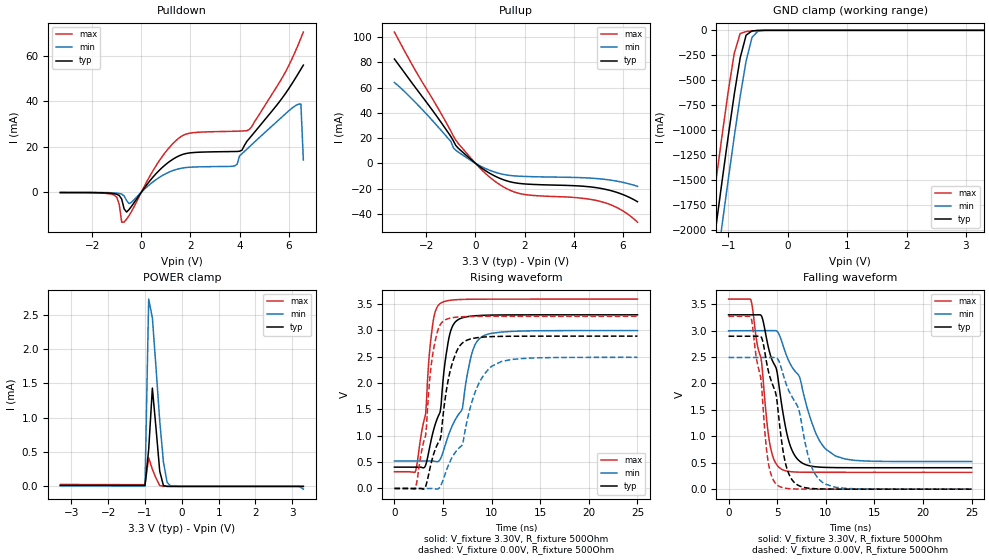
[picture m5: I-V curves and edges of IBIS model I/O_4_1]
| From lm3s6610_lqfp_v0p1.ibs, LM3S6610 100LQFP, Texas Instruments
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[Model]   I/O_4_1
Model_type   I/O
Vinl = 1.26
Vinh = 2.04
Vmeas = 1.65
| variable   typ   min   max
C_comp   9.739pF   9.739pF   9.739pF
[Model Spec]
Vinh+   1.91   1.78   2.04
Vinh-   1.90   1.76   2.03
Vinl+   1.40   1.27   1.54
Vinl-   1.39   1.26   1.53
| variable   typ   min   max
[Temperature Range]  25   85   -40
[Voltage Range]   3.3V   3.0V   3.6V
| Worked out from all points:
|   slope of the pulldown table from 0 to 0.495 V, typ, clamps not added: 71.5 ohm
|   slope of the pullup table from 0 to 0.495 V, typ, clamps not added: 71.6 ohm
|   GND clamp passes 1 mA (typ) near -0.48 V on its own axis
|   POWER clamp passes 1 mA (typ) near -0.73 V on its own axis
|   falling waveform, V_fixture 3.30V, R_fixture 500Ohm: 20-80 % time 2.03ns typ, 3.06ns min, 1.36ns max; typ from 3.3 V to 0.405 V
|   rising waveform, V_fixture 3.30V, R_fixture 500Ohm: 20-80 % time 1.61ns typ, 2.31ns min, 1.11ns max; typ from 0.405 V to 3.3 V
|   falling waveform, V_fixture 0.00V, R_fixture 500Ohm: 20-80 % time 1.75ns typ, 2.48ns min, 1.21ns max; typ from 2.89 V to 0 V
|   rising waveform, V_fixture 0.00V, R_fixture 500Ohm: 20-80 % time 1.94ns typ, 2.99ns min, 1.26ns max; typ from 0 V to 2.89 V
[Pulldown]
|  Voltage   I(typ)   I(min)   I(max)
-3.3V     -128.3uA   -72.81uA   -182.3uA
-1.1V     -636.5uA   -293.8uA   -1.284mA
-800mV    -2.996mA   -835.1uA   -13.2mA
-700mV    -7.355mA   -1.607mA   -13.16mA
-500mV    -7.628mA   -5mA       -10.33mA
700mV     9.309mA    6.304mA    13.37mA
1.6V      16.33mA    10.51mA    24.41mA
3.8V      17.94mA    11.61mA    26.87mA
4.4V      23.7mA     20mA       27.72mA
6.4V      52.42mA    38.8mA     65.24mA
6.5V      54.21mA    38.87mA    67.86mA
6.6V      56.01mA    14.21mA    70.56mA
[Pullup]
|  Voltage   I(typ)   I(min)   I(max)
-3.3V     82.57mA    63.94mA    103.9mA
-1.8V     43.25mA    34.86mA    52.68mA
-1V       21.14mA    17.2mA     25.44mA
-900mV    17.77mA    12.26mA    21.52mA
-800mV    14.06mA    10.32mA    18.34mA
100mV     -1.553mA   -1.117mA   -2.117mA
700mV     -9.22mA    -6.424mA   -12.9mA
1.3V      -14.07mA   -9.367mA   -20.37mA
1.9V      -16.2mA    -10.35mA   -24.39mA
5.2V      -20.26mA   -12.6mA    -30.84mA
5.9V      -24.02mA   -14.69mA   -36.54mA
6.6V      -30.45mA   -18.28mA   -46.68mA
[GND Clamp]
|  Voltage   I(typ)   I(min)   I(max)
-3.3V     -11.72A    -12.12A    -11.3A
-1.4V     -2.845A    -3.285A    -2.387A
-1.3V     -2.39A     -2.831A    -1.93A
-1.2V     -1.938A    -2.38A     -1.478A
-1.1V     -1.494A    -1.934A    -1.036A
-1V       -1.059A    -1.496A    -610.6mA
-900mV    -645mA     -1.069A    -232.9mA
-800mV    -277.1mA   -664.4mA   -31.59mA
-700mV    -48.56mA   -306.6mA   -12.09mA
-600mV    -5.558mA   -70.2mA    -6.272mA
-500mV    -1.167mA   -7.88mA    -2.167mA
3.3V      2.282nA    3.101uA    451.3pA
[POWER Clamp]
|  Voltage   I(typ)   I(min)   I(max)
-3.3V     15.18uA    8.315uA    27.48uA
-1V       14.14uA    7.74uA     25.63uA
-900mV    536uA      2.726mA    416.7uA
-800mV    1.43mA     2.454mA    247.6uA
-700mV    840.7uA    1.719mA    119.9uA
-600mV    221.2uA    951.5uA    11.58uA
-500mV    12.35uA    355.6uA    955.3nA
-400mV    305.2nA    58.59uA    44.3nA
-300mV    9.515nA    3.101uA    1.472nA
3.1V      1.302nA    -112.7nA   143.5pA
3.2V      1.207nA    -2.287uA   131.7pA
3.3V      -104.8pA   -40.34uA   119.2pA
[Ramp]
| variable   typ   min   max
dV/dt_f   1.73/2.03n   1.48/3.06n   1.97/1.36n
dV/dt_r   1.74/1.94n   1.49/2.99n   1.96/1.26n
R_load = 500Ohm
[Falling Waveform]
V_fixture = 3.30V
V_fixture_min = 3.00V
V_fixture_max = 3.60V
R_fixture = 500Ohm
|   Time   V(typ)   V(min)   V(max)
0s        3.297V     2.995V     3.595V
2.3ns     3.297V     2.998V     3.582V
3.4ns     3.272V     2.998V     2.405V
4.2ns     2.605V     2.998V     904.5mV
5.3ns     1.806V     2.883V     396.4mV
6.1ns     972.7mV    2.465V     338.5mV
6.9ns     612mV      2.217V     324.2mV
9.1ns     420.8mV    1.008V     318.9mV
11ns      407.6mV    627mV      318.6mV
25ns      405.4mV    522.4mV    318.5mV
[Rising Waveform]
V_fixture = 3.30V
V_fixture_min = 3.00V
V_fixture_max = 3.60V
R_fixture = 500Ohm
|   Time   V(typ)   V(min)   V(max)
0s        405.4mV    522.4mV    318.5mV
2.2ns     405.4mV    522.4mV    343mV
3.2ns     435.5mV    522.4mV    1.4V
3.6ns     760.2mV    522.3mV    2.571V
4ns       1.092V     521.2mV    3.195V
4.7ns     1.449V     551.8mV    3.511V
5.2ns     2.388V     807.4mV    3.554V
5.9ns     3.051V     1.172V     3.578V
9ns       3.287V     2.881V     3.595V
25ns      3.298V     2.999V     3.597V
[Falling Waveform]
V_fixture = 0.00V
V_fixture_min = 0.00V
V_fixture_max = 0.00V
R_fixture = 500Ohm
|   Time   V(typ)   V(min)   V(max)
0s        2.893V     2.49V      3.27V
2.3ns     2.893V     2.491V     3.256V
3.3ns     2.891V     2.491V     2.119V
4.1ns     2.228V     2.491V     489.2mV
5.1ns     1.475V     2.451V     66.07mV
5.7ns     623.8mV    2.118V     22.43mV
6.4ns     215mV      1.79V      7.113mV
8.5ns     13.49mV    445.2mV    479.7uV
9.7ns     3.634mV    124.5mV    177.5uV
25ns      17.27uV    28.07uV    10.86uV
[Rising Waveform]
V_fixture = 0.00V
V_fixture_min = 0.00V
V_fixture_max = 0.00V
R_fixture = 500Ohm
|   Time   V(typ)   V(min)   V(max)
0s        192.1uV    3.96mV     11.02uV
2.2ns     30.32uV    819.7uV    27.43mV
3.2ns     33.68mV    421.4uV    997.8mV
4ns       634.4mV    -846uV     2.619V
4.7ns     927.2mV    32.83mV    3.106V
5.1ns     1.54V      213mV      3.188V
6.7ns     2.703V     778mV      3.258V
8.4ns     2.86V      1.876V     3.267V
10ns      2.884V     2.319V     3.269V
25ns      2.893V     2.49V      3.269V
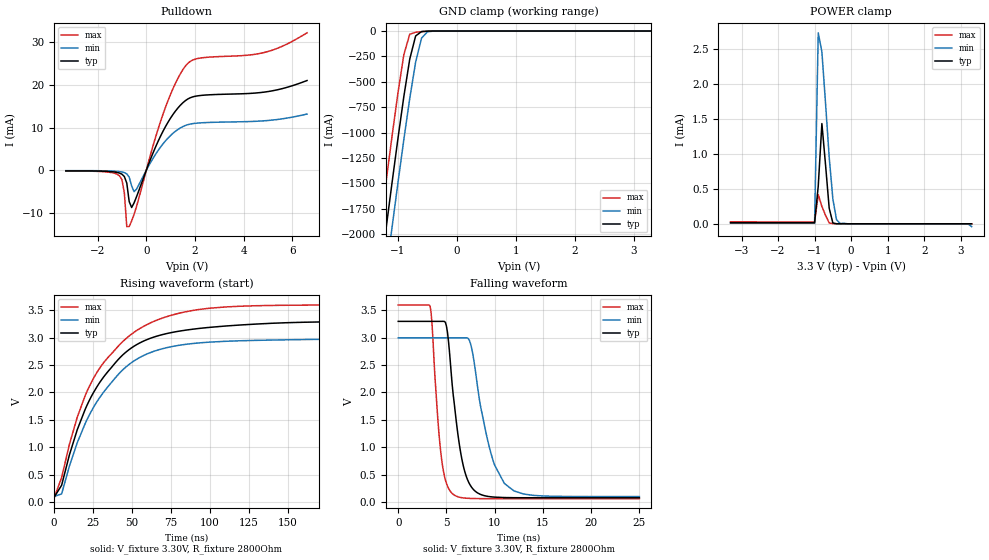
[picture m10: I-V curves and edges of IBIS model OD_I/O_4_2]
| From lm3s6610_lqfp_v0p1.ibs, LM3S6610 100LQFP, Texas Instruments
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[Model]   OD_I/O_4_2
Model_type   I/O_open_drain
Polarity   Inverting
Vinl = 1.26
Vinh = 2.04
Vmeas = 1.65
Rref = 2800
Vref = 3.3
| variable   typ   min   max
C_comp   9.739pF   9.739pF   9.739pF
[Model Spec]
Vinh+   1.91   1.78   2.04
Vinh-   1.90   1.76   2.03
Vinl+   1.40   1.27   1.54
Vinl-   1.39   1.26   1.53
| variable   typ   min   max
[Temperature Range]  25   85   -40
[Voltage Range]   3.3V   3.0V   3.6V
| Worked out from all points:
|   slope of the pulldown table from 0 to 0.495 V, typ, clamps not added: 71.5 ohm
|   GND clamp passes 1 mA (typ) near -0.48 V on its own axis
|   POWER clamp passes 1 mA (typ) near -0.73 V on its own axis
|   falling waveform, V_fixture 3.30V, R_fixture 2800Ohm: 20-80 % time 1.32ns typ, 2ns min, 885ps max; typ from 3.3 V to 0.075 V
|   rising waveform, V_fixture 3.30V, R_fixture 2800Ohm: 20-80 % time 34.3ns typ, 34ns min, 35.2ns max; typ from 0.075 V to 3.3 V
[Pulldown]
|  Voltage   I(typ)   I(min)   I(max)
-3.3V     -128.3uA   -72.81uA   -182.3uA
-1.1V     -636.5uA   -293.8uA   -1.284mA
-900mV    -1.443mA   -530.4uA   -5.27mA
-800mV    -2.996mA   -835.1uA   -13.2mA
-700mV    -7.355mA   -1.607mA   -13.16mA
-600mV    -8.716mA   -3.66mA    -11.87mA
-500mV    -7.628mA   -5mA       -10.33mA
700mV     9.309mA    6.304mA    13.37mA
1.2V      13.92mA    9.18mA     20.46mA
1.7V      16.72mA    10.71mA    25.07mA
4.9V      18.4mA     11.65mA    27.73mA
6.6V      21.07mA    13.21mA    32.27mA
[GND Clamp]
|  Voltage   I(typ)   I(min)   I(max)
-3.3V     -11.72A    -12.12A    -11.3A
-1.4V     -2.845A    -3.285A    -2.387A
-1.3V     -2.39A     -2.831A    -1.93A
-1.2V     -1.938A    -2.38A     -1.478A
-1.1V     -1.494A    -1.934A    -1.036A
-1V       -1.059A    -1.496A    -610.6mA
-900mV    -645mA     -1.069A    -232.9mA
-800mV    -277.1mA   -664.4mA   -31.59mA
-700mV    -48.56mA   -306.6mA   -12.09mA
-600mV    -5.558mA   -70.2mA    -6.272mA
-500mV    -1.167mA   -7.88mA    -2.167mA
3.3V      2.282nA    3.101uA    451.3pA
[POWER Clamp]
|  Voltage   I(typ)   I(min)   I(max)
-3.3V     15.18uA    8.315uA    27.48uA
-1V       14.14uA    7.74uA     25.63uA
-900mV    536uA      2.726mA    416.7uA
-800mV    1.43mA     2.454mA    247.6uA
-700mV    840.7uA    1.719mA    119.9uA
-600mV    221.2uA    951.5uA    11.58uA
-500mV    12.35uA    355.6uA    955.3nA
-400mV    305.2nA    58.59uA    44.3nA
-300mV    9.515nA    3.101uA    1.472nA
3.1V      1.302nA    -112.7nA   143.5pA
3.2V      1.207nA    -2.287uA   131.7pA
3.3V      -104.8pA   -40.34uA   119.2pA
[Ramp]
| variable   typ   min   max
dV/dt_f   1.93/1.32n   1.74/2.00n   2.12/0.89n
dV/dt_r   1.93/34.28n   1.74/34.01n   2.12/35.19n
R_load = 2800Ohm
[Falling Waveform]
V_fixture = 3.30V
V_fixture_min = 3.00V
V_fixture_max = 3.60V
R_fixture = 2800Ohm
|   Time   V(typ)   V(min)   V(max)
0s        3.3V       2.999V     3.6V
3.3ns     3.3V       2.999V     3.58V
4.5ns     3.3V       2.999V     778.2mV
5.1ns     3.106V     2.999V     293mV
5.7ns     1.96V      2.999V     139mV
6.5ns     875.4mV    2.999V     79.96mV
7.3ns     360.9mV    2.976V     64.99mV
9.4ns     98.12mV    1.034V     59.11mV
11ns      79.42mV    338.6mV    58.76mV
25ns      75.03mV    97.58mV    58.6mV
[Rising Waveform]
V_fixture = 3.30V
V_fixture_min = 3.00V
V_fixture_max = 3.60V
R_fixture = 2800Ohm
|   Time   V(typ)   V(min)   V(max)
0s        74.96mV    97.49mV    58.55mV
5ns       304.3mV    145.8mV    444.4mV
10ns      859.9mV    656.9mV    1.053V
15ns      1.317V     1.08V      1.546V
25ns      1.977V     1.706V     2.235V
43ns      2.653V     2.38V      2.896V
60ns      2.969V     2.707V     3.244V
82ns      3.128V     2.869V     3.459V
110ns     3.214V     2.935V     3.562V
250ns     3.298V     2.994V     3.599V
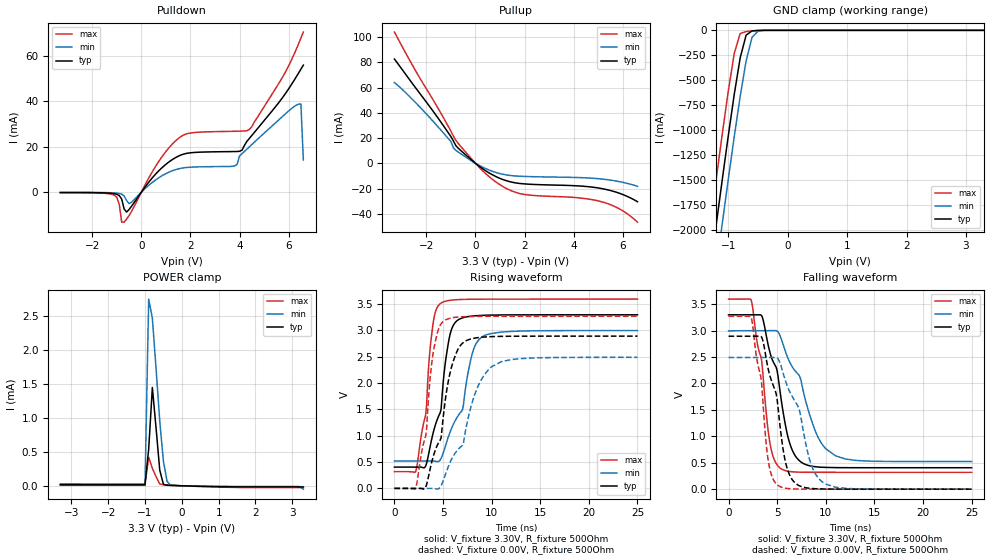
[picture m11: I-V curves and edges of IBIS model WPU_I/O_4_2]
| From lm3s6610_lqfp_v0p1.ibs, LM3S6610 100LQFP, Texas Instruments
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[Model]   WPU_I/O_4_2
Model_type   I/O
Vinl = 1.26
Vinh = 2.04
Vmeas = 1.65
| variable   typ   min   max
C_comp   9.739pF   9.739pF   9.739pF
[Model Spec]
Vinh+   1.91   1.78   2.04
Vinh-   1.90   1.76   2.03
Vinl+   1.40   1.27   1.54
Vinl-   1.39   1.26   1.53
| variable   typ   min   max
[Temperature Range]  25   85   -40
[Voltage Range]   3.3V   3.0V   3.6V
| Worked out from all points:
|   slope of the pulldown table from 0 to 0.495 V, typ, clamps not added: 71.5 ohm
|   slope of the pullup table from 0 to 0.495 V, typ, clamps not added: 71.7 ohm
|   GND clamp passes 1 mA (typ) near -0.48 V on its own axis
|   POWER clamp passes 1 mA (typ) near -0.73 V on its own axis
|   falling waveform, V_fixture 3.30V, R_fixture 500Ohm: 20-80 % time 2.03ns typ, 3.06ns min, 1.36ns max; typ from 3.3 V to 0.405 V
|   rising waveform, V_fixture 3.30V, R_fixture 500Ohm: 20-80 % time 1.62ns typ, 2.31ns min, 1.11ns max; typ from 0.405 V to 3.3 V
|   falling waveform, V_fixture 0.00V, R_fixture 500Ohm: 20-80 % time 1.75ns typ, 2.48ns min, 1.21ns max; typ from 2.89 V to 0 V
|   rising waveform, V_fixture 0.00V, R_fixture 500Ohm: 20-80 % time 1.94ns typ, 2.99ns min, 1.26ns max; typ from 0 V to 2.89 V
[Pulldown]
|  Voltage   I(typ)   I(min)   I(max)
-3.3V     -128.1uA   -72.69uA   -182uA
-1.1V     -635.5uA   -293.2uA   -1.281mA
-800mV    -2.994mA   -834.1uA   -13.19mA
-700mV    -7.352mA   -1.606mA   -13.14mA
-500mV    -7.614mA   -4.997mA   -10.31mA
700mV     9.325mA    6.314mA    13.4mA
1.6V      16.34mA    10.52mA    24.44mA
3.8V      17.93mA    11.6mA     26.87mA
4.4V      23.7mA     20mA       27.71mA
6.4V      52.42mA    38.8mA     65.24mA
6.5V      54.21mA    38.87mA    67.86mA
6.6V      56.01mA    14.21mA    70.56mA
[Pullup]
|  Voltage   I(typ)   I(min)   I(max)
-3.3V     82.57mA    63.94mA    103.9mA
-1.8V     43.25mA    34.86mA    52.68mA
-1V       21.14mA    17.2mA     25.44mA
-900mV    17.77mA    12.24mA    21.52mA
-800mV    14.04mA    10.31mA    18.34mA
100mV     -1.551mA   -1.116mA   -2.115mA
700mV     -9.21mA    -6.417mA   -12.88mA
1.3V      -14.06mA   -9.358mA   -20.34mA
1.9V      -16.18mA   -10.35mA   -24.37mA
5.2V      -20.25mA   -12.6mA    -30.83mA
5.9V      -24.01mA   -14.69mA   -36.53mA
6.6V      -30.45mA   -18.28mA   -46.68mA
[GND Clamp]
|  Voltage   I(typ)   I(min)   I(max)
-3.3V     -11.72A    -12.12A    -11.3A
-1.4V     -2.845A    -3.285A    -2.387A
-1.3V     -2.39A     -2.831A    -1.93A
-1.2V     -1.938A    -2.38A     -1.478A
-1.1V     -1.494A    -1.934A    -1.036A
-1V       -1.059A    -1.496A    -610.6mA
-900mV    -645mA     -1.069A    -232.9mA
-800mV    -277.1mA   -664.4mA   -31.6mA
-700mV    -48.56mA   -306.6mA   -12.11mA
-600mV    -5.565mA   -70.2mA    -6.295mA
-500mV    -1.181mA   -7.883mA   -2.191mA
3.3V      2.282nA    6.919uA    -6.845uA
[POWER Clamp]
|  Voltage   I(typ)   I(min)   I(max)
-3.3V     15.18uA    8.315uA    27.48uA
-1V       14.14uA    7.74uA     25.63uA
-900mV    539.2uA    2.746mA    419.4uA
-800mV    1.446mA    2.463mA    255uA
-700mV    851uA      1.726mA    135.8uA
-600mV    231.3uA    957.3uA    27.23uA
-500mV    21.69uA    361.2uA    14.14uA
-400mV    7.764uA    63.51uA    10.49uA
-300mV    5.5uA      6.919uA    7.727uA
3.1V      -16.64uA   -9.947uA   -27.43uA
3.2V      -16.65uA   -12.11uA   -27.44uA
3.3V      -16.65uA   -49.87uA   -27.45uA
[Ramp]
| variable   typ   min   max
dV/dt_f   1.73/2.03n   1.48/3.06n   1.97/1.36n
dV/dt_r   1.74/1.94n   1.49/2.99n   1.96/1.26n
R_load = 500Ohm
[Falling Waveform]
V_fixture = 3.30V
V_fixture_min = 3.00V
V_fixture_max = 3.60V
R_fixture = 500Ohm
|   Time   V(typ)   V(min)   V(max)
0s        3.297V     2.994V     3.595V
2.3ns     3.297V     2.997V     3.59V
3.4ns     3.283V     2.998V     2.441V
4.3ns     2.559V     2.998V     826.9mV
5.3ns     1.846V     2.901V     400mV
6.1ns     994.8mV    2.482V     339.4mV
6.9ns     620.2mV    2.226V     324.5mV
9.2ns     419.7mV    985.1mV    318.8mV
11ns      407.7mV    630.6mV    318.6mV
25ns      405.4mV    522.4mV    318.5mV
[Rising Waveform]
V_fixture = 3.30V
V_fixture_min = 3.00V
V_fixture_max = 3.60V
R_fixture = 500Ohm
|   Time   V(typ)   V(min)   V(max)
0s        405.4mV    522.4mV    318.5mV
2.2ns     405.4mV    522.4mV    327.6mV
3.2ns     420.5mV    522.4mV    1.383V
4ns       1.067V     522.1mV    3.164V
4.8ns     1.506V     570.5mV    3.521V
5.3ns     2.474V     838.3mV    3.558V
6ns       3.077V     1.194V     3.579V
7ns       3.239V     1.496V     3.59V
9ns       3.287V     2.875V     3.595V
25ns      3.298V     2.999V     3.597V
[Falling Waveform]
V_fixture = 0.00V
V_fixture_min = 0.00V
V_fixture_max = 0.00V
R_fixture = 500Ohm
|   Time   V(typ)   V(min)   V(max)
0s        2.893V     2.49V      3.27V
2.3ns     2.893V     2.491V     3.264V
3.4ns     2.877V     2.491V     2.005V
4.1ns     2.254V     2.491V     517.1mV
5.1ns     1.527V     2.462V     69.45mV
5.7ns     654.7mV    2.142V     23.49mV
6.4ns     225.2mV    1.803V     7.427mV
8.5ns     14.01mV    465.6mV    487.9uV
9.8ns     3.391mV    117.3mV    171.8uV
25ns      17.18uV    28.46uV    11.66uV
[Rising Waveform]
V_fixture = 0.00V
V_fixture_min = 0.00V
V_fixture_max = 0.00V
R_fixture = 500Ohm
|   Time   V(typ)   V(min)   V(max)
0s        185.4uV    3.802mV    10.74uV
2.2ns     29.2uV     789.9uV    11.85mV
3.3ns     69.38mV    374.3uV    1.1V
4ns       612.6mV    -32.19uV   2.589V
4.8ns     961.2mV    50.1mV     3.127V
5.1ns     1.486V     187.8mV    3.184V
6.7ns     2.693V     769.4mV    3.258V
8.4ns     2.859V     1.853V     3.267V
10ns      2.884V     2.312V     3.269V
25ns      2.893V     2.49V      3.269V
